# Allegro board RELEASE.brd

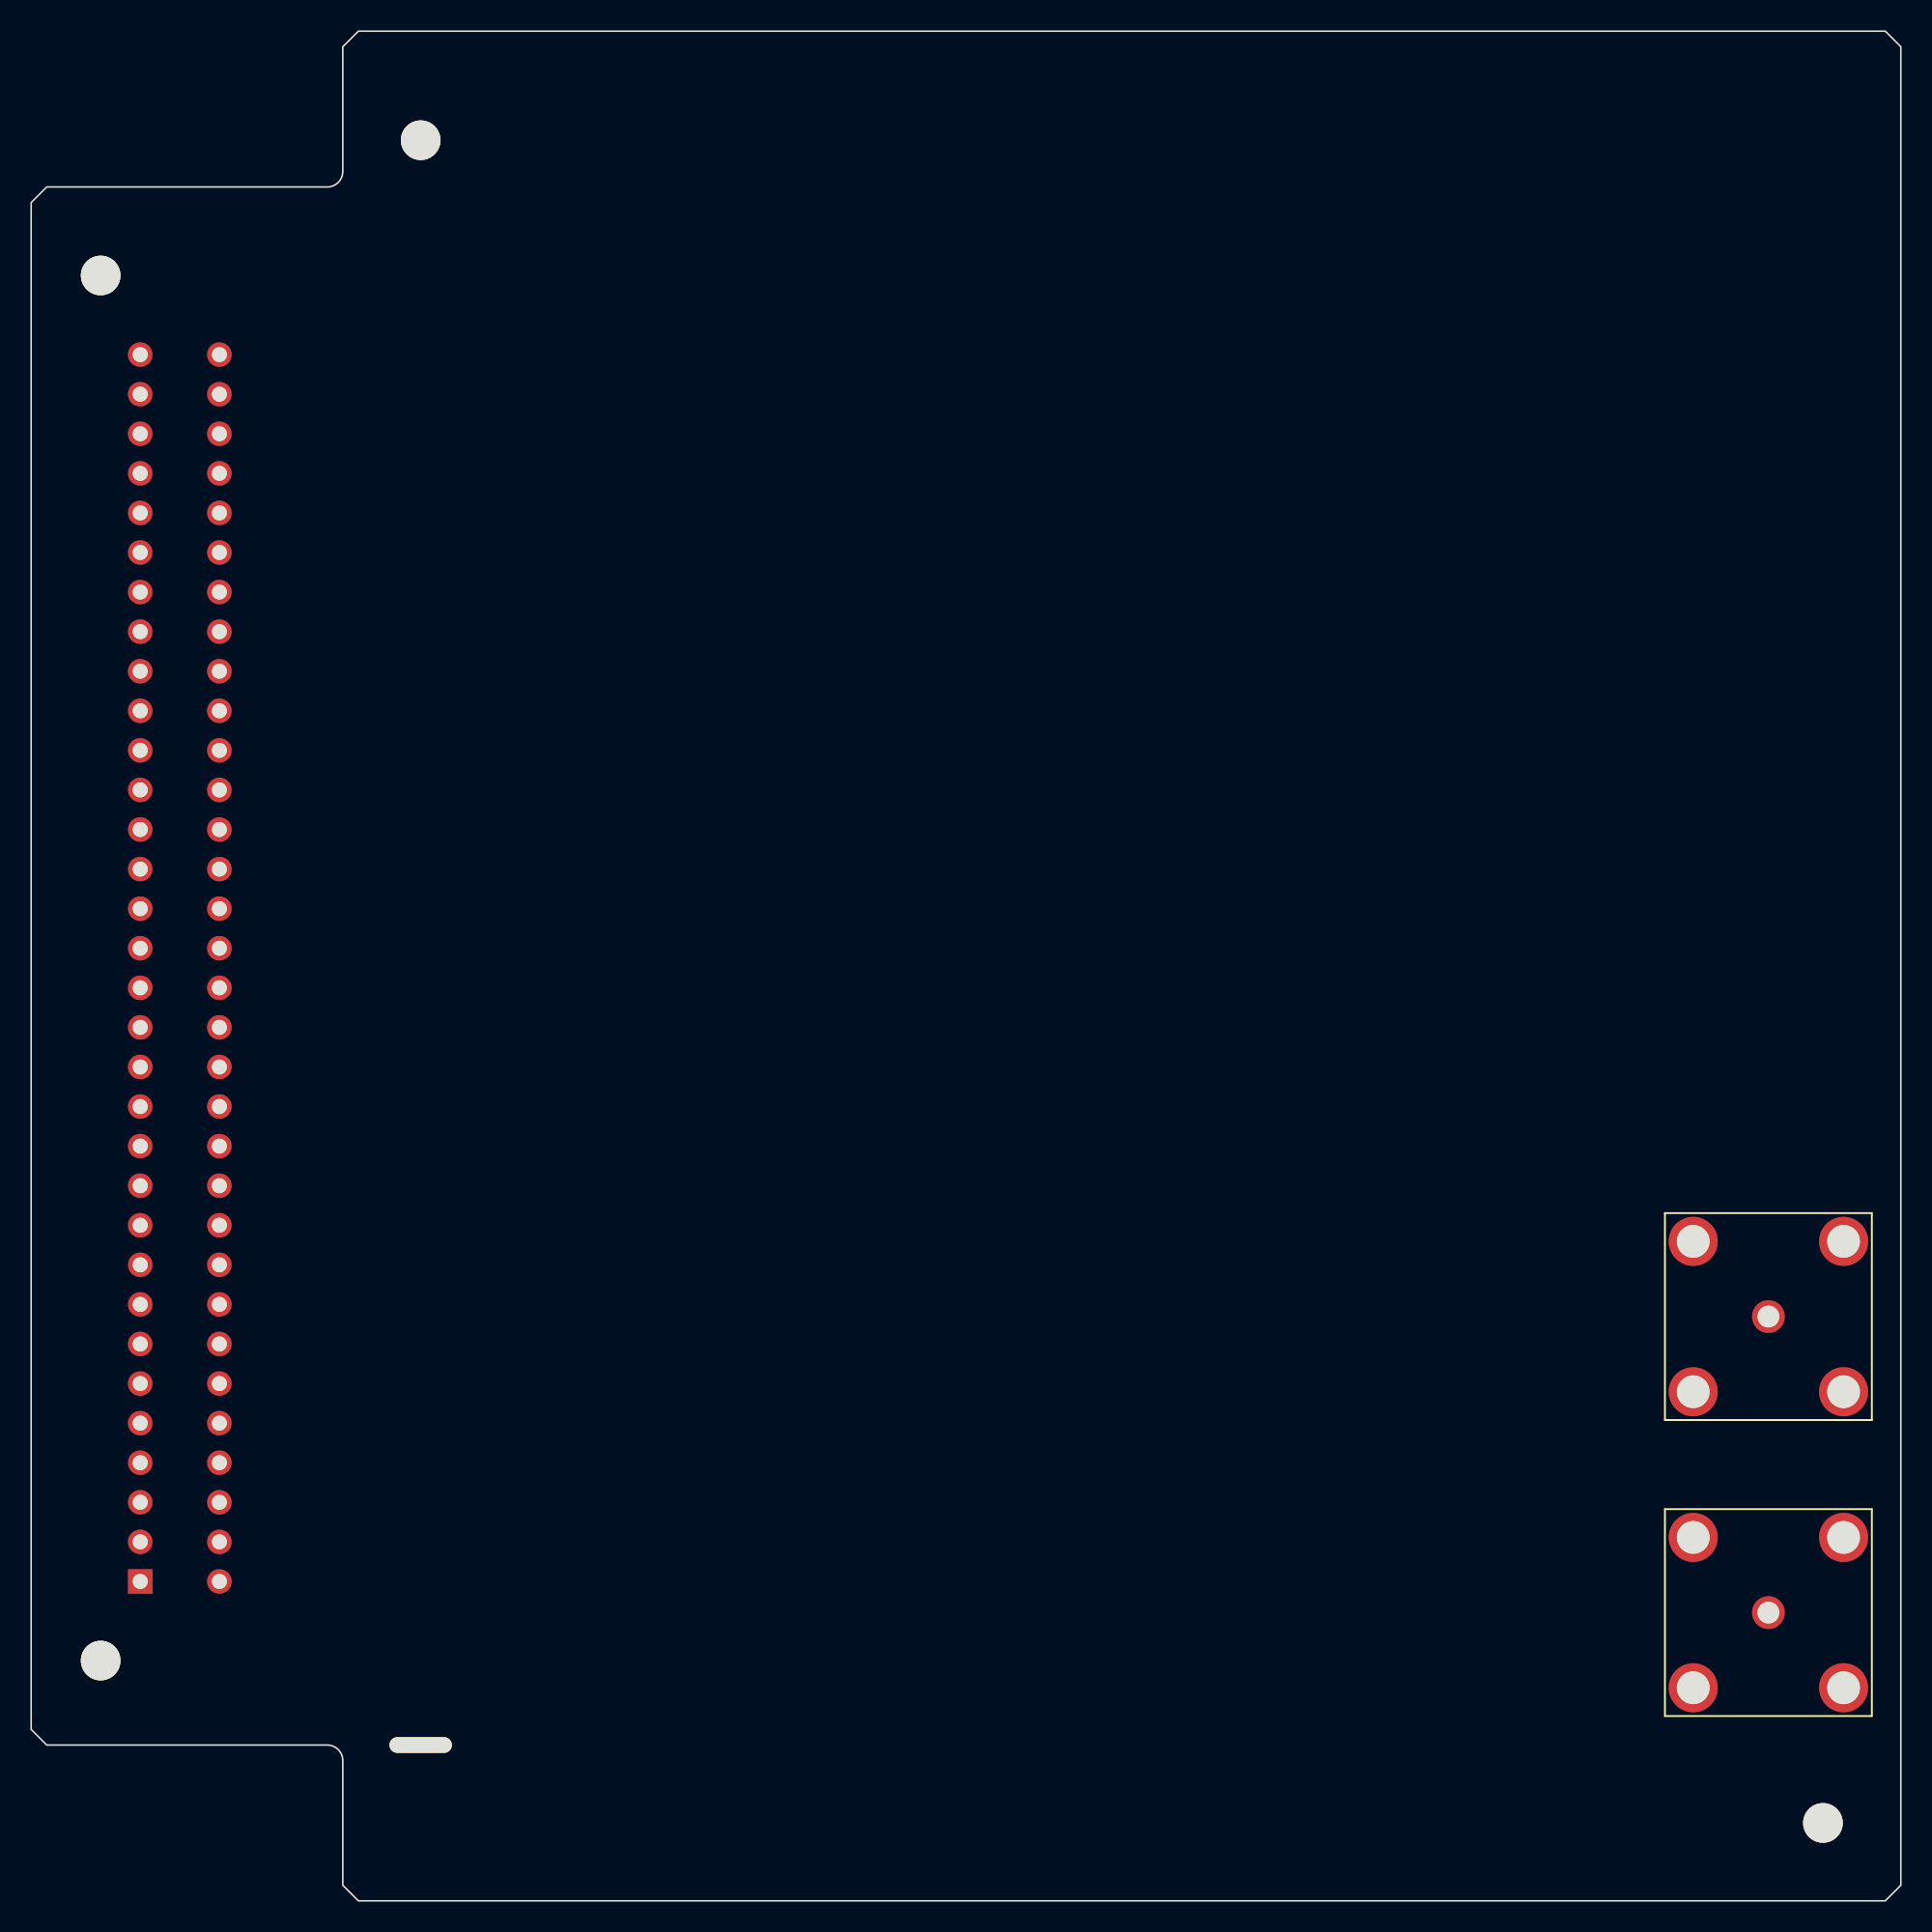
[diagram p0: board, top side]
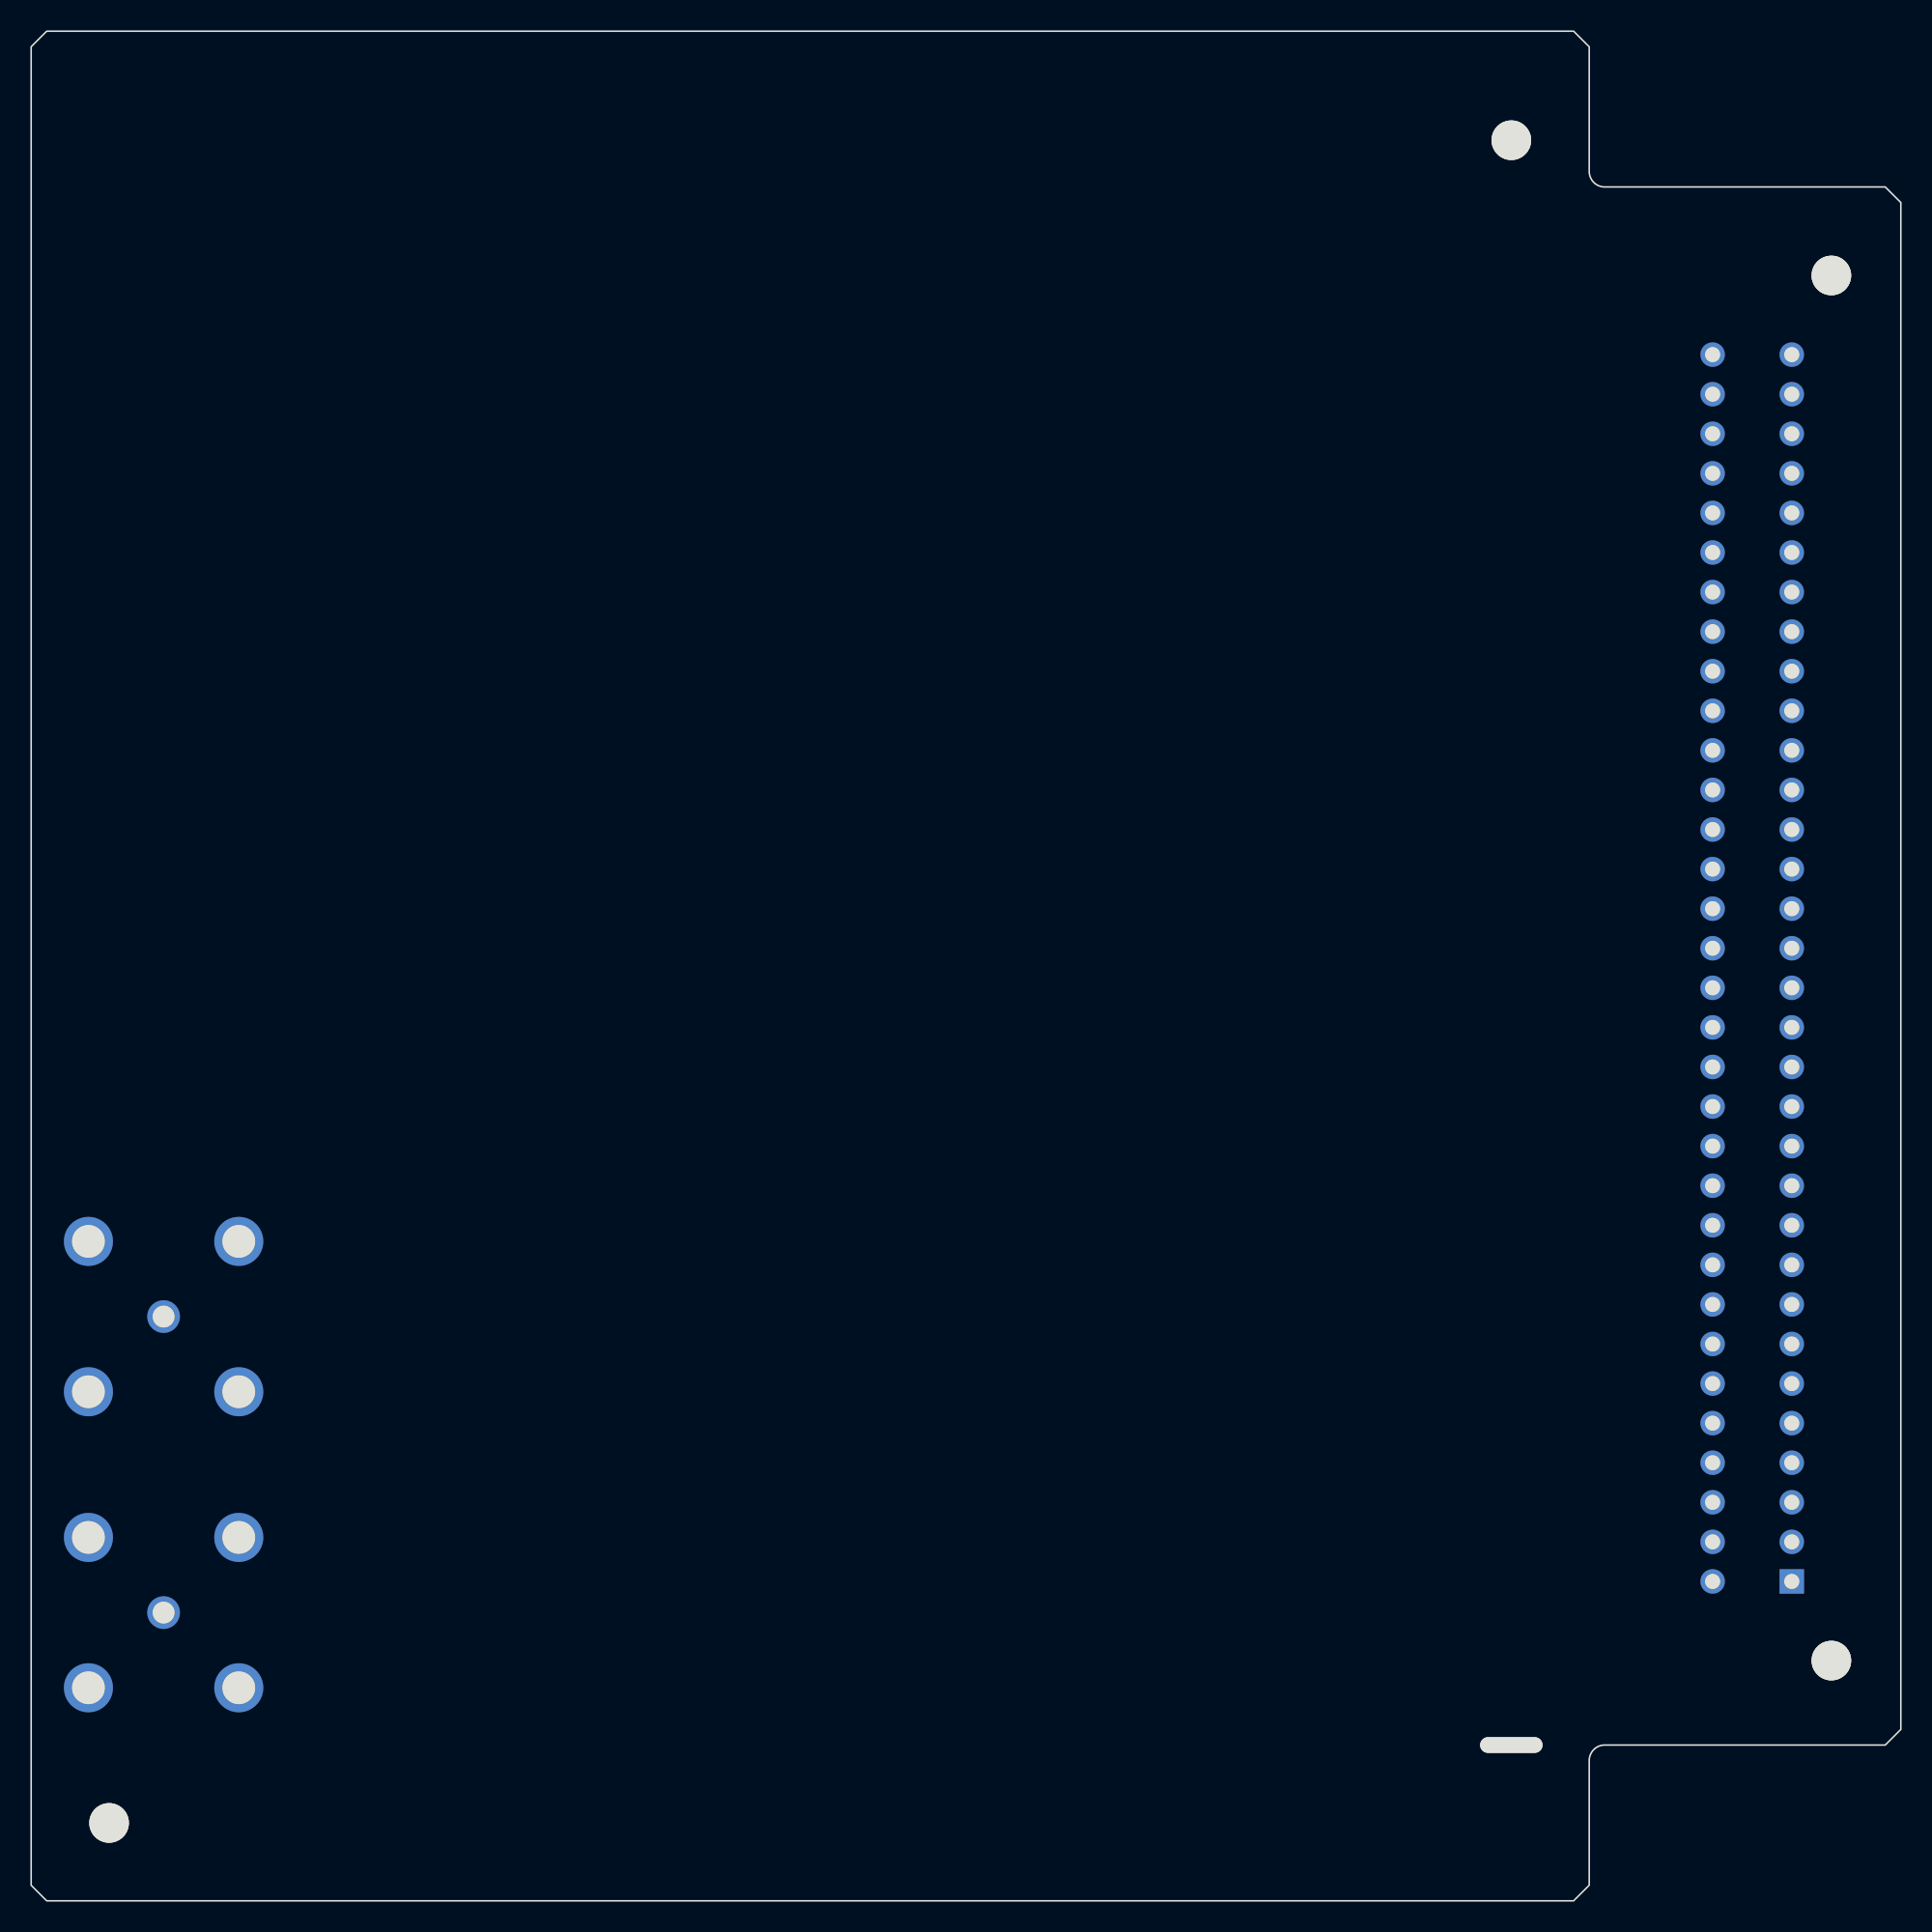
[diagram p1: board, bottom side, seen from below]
Outline 120 x 120 mm; copper layers: TOP, GND1, VCC1, VCC2, GND2, BOTTOM. Coordinates in mm from the lower left corner of the outline.

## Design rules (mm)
constraint set DEFAULT: min track width 0.127
net group MEMORY[0..28]: nets MEMORY.RA0 MEMORY.RA1 MEMORY.RA2 MEMORY.RA3 MEMORY.RA4 MEMORY.RA5 MEMORY.RA6 MEMORY.RA7 MEMORY.RA8 MEMORY.RA9 MEMORY.RA10 MEMORY.RA11 MEMORY.RA12 MEMORY.RA13 MEMORY.RA14 MEMORY.RA15 MEMORY.RCS0 MEMORY.RCS1 MEMORY.RCS2 MEMORY.RCS3 MEMORY.RD0 MEMORY.RD1 MEMORY.RD2 MEMORY.RD3 MEMORY.RD4 MEMORY.RD5 MEMORY.RD6 MEMORY.RD7 MEMORY.RWE
net group POWER: nets AGND GND_EARTH V12N V+12

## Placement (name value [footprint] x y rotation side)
J*  -  [unnamed#4]  7 20.5 0 top
NOREF  -  [unnamed]  25 10 0 top
NOREF#2  -  [#3]  19.76 110.35 0 top
NOREF#3  -  [#3]  25 10 0 top
NOREF#4  -  [#3]  25 10 90 top
NOREF#5  -  [#3]  25 10 90 top
NOREF#6  -  [#3]  25 10 0 top
NOREF#7  -  [#3]  -71.52 -89.06 0 top
NOREF#8  -  [#3]  0 15.3 0 top
NOREF#9  -  [#3]  20 4.47 0 top
NOREF#10  -  [#3]  197.72 152.24 0 top
NOREF#11  -  [#3]  119.43 119.57 0 top
NOREF#12  -  [#3]  25 10 90 top
NOREF#13  -  [#3]  25.27 0 90 top
REF  -  [unnamed#2]  111.5 37.5 0 top
REF#2  -  [unnamed#2]  111.5 18.5 0 top

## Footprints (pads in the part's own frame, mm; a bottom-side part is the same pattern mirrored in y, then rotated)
unnamed
  round 2.54 hole 2.794 unplated: (0,103) (90,-5)
  oval 4x1 hole 5x1.5 unplated: (0,0)
unnamed#2
  round 2.1 hole 1.4: 1(0,0)
  round 3.15 hole 2.1: 2(-4.825,4.825) 3(4.825,4.825) 4(4.825,-4.825) 5(-4.825,-4.825)
unnamed#4
  round 2.54 hole 2.794 unplated: (-2.54,83.82) (-2.54,-5.08)
  rect 1.575x1.575 hole 0.965: 1(0,0)
  round 1.575 hole 0.965: 2(0,2.54) 3(0,5.08) 4(0,7.62) 5(0,10.16) 6(0,12.7) 7(0,15.24) 8(0,17.78) 9(0,20.32) 10(0,22.86) 11(0,25.4) 12(0,27.94) 13(0,30.48) 14(0,33.02) 15(0,35.56) 16(0,38.1) 17(0,40.64) 18(0,43.18) 19(0,45.72) 20(0,48.26) 21(0,50.8) 22(0,53.34) 23(0,55.88) 24(0,58.42) 25(0,60.96) 26(0,63.5) 27(0,66.04) 28(0,68.58) 29(0,71.12) 30(0,73.66) 31(0,76.2) 32(0,78.74) 33(5.08,0) 34(5.08,2.54) 35(5.08,5.08) 36(5.08,7.62) 37(5.08,10.16) 38(5.08,12.7) 39(5.08,15.24) 40(5.08,17.78) 41(5.08,20.32) 42(5.08,22.86) 43(5.08,25.4) 44(5.08,27.94) 45(5.08,30.48) 46(5.08,33.02) 47(5.08,35.56) 48(5.08,38.1) 49(5.08,40.64) 50(5.08,43.18) 51(5.08,45.72) 52(5.08,48.26) 53(5.08,50.8) 54(5.08,53.34) 55(5.08,55.88) 56(5.08,58.42) 57(5.08,60.96) 58(5.08,63.5) 59(5.08,66.04) 60(5.08,68.58) 61(5.08,71.12) 62(5.08,73.66) 63(5.08,76.2) 64(5.08,78.74)

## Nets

Pads without a net: J* 1 2 3 4 5 6 7 8 9 10 11 12 13 14 15 16 17 18 19 20 21 22 23 24 25 26 27 28 29 30 31 32 33 34 35 36 37 38 39 40 41 42 43 44 45 46 47 48 49 50 51 52 53 54 55 56 57 58 59 60 61 62 63 64; REF 1 2 3 4 5; REF#2 1 2 3 4 5
